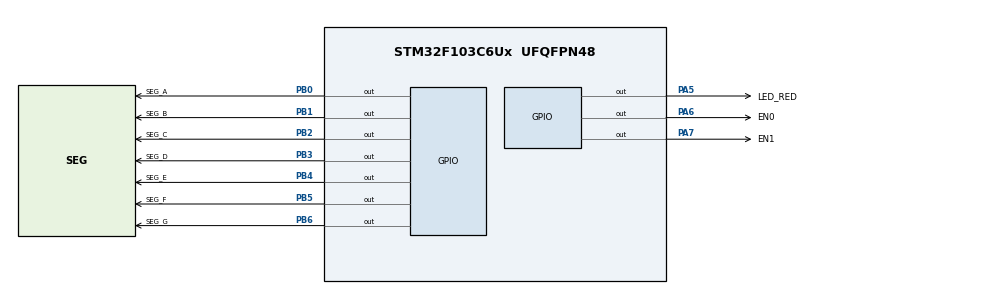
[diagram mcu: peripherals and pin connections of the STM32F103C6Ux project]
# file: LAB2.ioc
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Mcu.Family=STM32F1
Mcu.Name=STM32F103C6Ux
Mcu.Package=UFQFPN48
NVIC.PriorityGroup=NVIC_PRIORITYGROUP_4
NVIC.TIM2_IRQn=true\:0\:0\:false\:false\:true\:true\:true
PA5.GPIO_Label=LED_RED
PA5.Signal=GPIO_Output
PA6.GPIO_Label=EN0
PA6.Signal=GPIO_Output
PA7.GPIO_Label=EN1
PA7.Signal=GPIO_Output
PB0.GPIO_Label=SEG_A
PB0.Signal=GPIO_Output
PB1.GPIO_Label=SEG_B
PB1.Signal=GPIO_Output
PB2.GPIO_Label=SEG_C
PB2.Signal=GPIO_Output
PB3.GPIO_Label=SEG_D
PB3.Signal=GPIO_Output
PB4.GPIO_Label=SEG_E
PB4.Signal=GPIO_Output
PB5.GPIO_Label=SEG_F
PB5.Signal=GPIO_Output
PB6.GPIO_Label=SEG_G
PB6.Signal=GPIO_Output
ProjectManager.HeapSize=0x200
ProjectManager.StackSize=0x400
ProjectManager.TargetToolchain=STM32CubeIDE
RCC.APB1Freq_Value=8000000
RCC.APB2Freq_Value=8000000
TIM2.Period=9
TIM2.Prescaler=7999
VP_SYS_VS_ND.Mode=No_Debug
VP_TIM2_VS_ClockSourceINT.Mode=Internal
board=custom

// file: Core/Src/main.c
/* USER CODE BEGIN Header */
/**
  ******************************************************************************
  * @file           : main.c
  * @brief          : Main program body
  ******************************************************************************
  * @attention
  *
  * <h2><center>&copy; Copyright (c) 2025 STMicroelectronics.
  * All rights reserved.</center></h2>
  *
  * This software component is licensed by ST under BSD 3-Clause license,
  * the "License"; You may not use this file except in compliance with the
  * License. You may obtain a copy of the License at:
  *                        opensource.org/licenses/BSD-3-Clause
  *
  ******************************************************************************
  */
/* USER CODE END Header */
#include "main.h"

/* USER CODE BEGIN Includes */
#include "software_timer.h"
/* USER CODE END Includes */

TIM_HandleTypeDef htim2;

void SystemClock_Config(void);
static void MX_GPIO_Init(void);
static void MX_TIM2_Init(void);
/* USER CODE BEGIN PFP */
void updateClockBuffer(void);
void update7SEG(int index);
/* USER CODE END PFP */

/* USER CODE BEGIN 0 */
const int MAX_LED = 4;
int index_led = 0;
int led_buffer[4] = {0, 0, 0, 0};

int hour = 0, minute = 0, second = 0;
/* USER CODE END 0 */

int main(void)
{

  /* MCU Configuration--------------------------------------------------------*/

  /* Reset of all peripherals, Initializes the Flash interface and the Systick. */
  HAL_Init();

  /* Configure the system clock */
  SystemClock_Config();

  /* Initialize all configured peripherals */
  MX_GPIO_Init();
  MX_TIM2_Init();
  /* USER CODE BEGIN 2 */
  HAL_TIM_Base_Start_IT(&htim2);
  /* USER CODE END 2 */

  /* Infinite loop */
  /* USER CODE BEGIN WHILE */
  hour = 15; minute = 8; second = 50;
  updateClockBuffer();
  HAL_GPIO_WritePin(EN0_GPIO_Port, EN0_Pin, SET);
  HAL_GPIO_WritePin(EN1_GPIO_Port, EN1_Pin, SET);
  HAL_GPIO_WritePin(EN2_GPIO_Port, EN2_Pin, SET);
  HAL_GPIO_WritePin(EN3_GPIO_Port, EN3_Pin, SET);
  setTimer (0, 100); // LED Blinky
  setTimer (1, 100); // DOT
  setTimer (2, 100); // UPDATE TIME
  setTimer (3, 25);  // UPDATE 7SEG
  while (1)
  {
	  if (isTimerExpired(0)) {
		  HAL_GPIO_TogglePin(LED_RED_GPIO_Port, LED_RED_Pin);
		  setTimer (0, 100);
	  }

	  if (isTimerExpired(1)) {
		  HAL_GPIO_TogglePin(DOT_GPIO_Port, DOT_Pin);
		  setTimer (1, 100);
	  }

	  if (isTimerExpired(2)) {
		  second++;
		  if (second >= 60) {
			  second = 0;
			  minute++;
		  }
		  if (minute >= 60) {
			  minute = 0;
			  hour++;
		  }
		  if (hour >= 24) {
			  hour = 0;
		  }
		  updateClockBuffer();
		  setTimer (2, 100);
	  }

	  if (isTimerExpired(3)) {
		  update7SEG(index_led);
		  index_led++;
		  if (index_led >= MAX_LED) {
			  index_led = 0;
		  }
		  setTimer (3, 25);
	  }
    /* USER CODE END WHILE */

  }
}

void SystemClock_Config(void)
{
  RCC_OscInitTypeDef RCC_OscInitStruct = {0};
  RCC_ClkInitTypeDef RCC_ClkInitStruct = {0};

  /** Initializes the RCC Oscillators according to the specified parameters
  * in the RCC_OscInitTypeDef structure.
  */
  RCC_OscInitStruct.OscillatorType = RCC_OSCILLATORTYPE_HSI;
  RCC_OscInitStruct.HSIState = RCC_HSI_ON;
  RCC_OscInitStruct.HSICalibrationValue = RCC_HSICALIBRATION_DEFAULT;
  RCC_OscInitStruct.PLL.PLLState = RCC_PLL_NONE;
  if (HAL_RCC_OscConfig(&RCC_OscInitStruct) != HAL_OK)
  {
    Error_Handler();
  }
  /** Initializes the CPU, AHB and APB buses clocks
  */
  RCC_ClkInitStruct.ClockType = RCC_CLOCKTYPE_HCLK|RCC_CLOCKTYPE_SYSCLK
                              |RCC_CLOCKTYPE_PCLK1|RCC_CLOCKTYPE_PCLK2;
  RCC_ClkInitStruct.SYSCLKSource = RCC_SYSCLKSOURCE_HSI;
  RCC_ClkInitStruct.AHBCLKDivider = RCC_SYSCLK_DIV1;
  RCC_ClkInitStruct.APB1CLKDivider = RCC_HCLK_DIV1;
  RCC_ClkInitStruct.APB2CLKDivider = RCC_HCLK_DIV1;

  if (HAL_RCC_ClockConfig(&RCC_ClkInitStruct, FLASH_LATENCY_0) != HAL_OK)
  {
    Error_Handler();
  }
}

static void MX_TIM2_Init(void)
{

  TIM_ClockConfigTypeDef sClockSourceConfig = {0};
  TIM_MasterConfigTypeDef sMasterConfig = {0};

  htim2.Instance = TIM2;
  htim2.Init.Prescaler = 7999;
  htim2.Init.CounterMode = TIM_COUNTERMODE_UP;
  htim2.Init.Period = 9;
  htim2.Init.ClockDivision = TIM_CLOCKDIVISION_DIV1;
  htim2.Init.AutoReloadPreload = TIM_AUTORELOAD_PRELOAD_DISABLE;
  if (HAL_TIM_Base_Init(&htim2) != HAL_OK)
  {
    Error_Handler();
  }
  sClockSourceConfig.ClockSource = TIM_CLOCKSOURCE_INTERNAL;
  if (HAL_TIM_ConfigClockSource(&htim2, &sClockSourceConfig) != HAL_OK)
  {
    Error_Handler();
  }
  sMasterConfig.MasterOutputTrigger = TIM_TRGO_RESET;
  sMasterConfig.MasterSlaveMode = TIM_MASTERSLAVEMODE_DISABLE;
  if (HAL_TIMEx_MasterConfigSynchronization(&htim2, &sMasterConfig) != HAL_OK)
  {
    Error_Handler();
  }

}

static void MX_GPIO_Init(void)
{
  GPIO_InitTypeDef GPIO_InitStruct = {0};

  /* GPIO Ports Clock Enable */
  __HAL_RCC_GPIOA_CLK_ENABLE();
  __HAL_RCC_GPIOB_CLK_ENABLE();

  /*Configure GPIO pin Output Level */
  HAL_GPIO_WritePin(GPIOA, DOT_Pin|LED_RED_Pin|EN0_Pin|EN1_Pin
                          |EN2_Pin|EN3_Pin, GPIO_PIN_RESET);

  /*Configure GPIO pin Output Level */
  HAL_GPIO_WritePin(GPIOB, SEG_A_Pin|SEG_B_Pin|SEG_C_Pin|SEG_D_Pin
                          |SEG_E_Pin|SEG_F_Pin|SEG_G_Pin, GPIO_PIN_RESET);

  /*Configure GPIO pins : DOT_Pin LED_RED_Pin EN0_Pin EN1_Pin
                           EN2_Pin EN3_Pin */
  GPIO_InitStruct.Pin = DOT_Pin|LED_RED_Pin|EN0_Pin|EN1_Pin
                          |EN2_Pin|EN3_Pin;
  GPIO_InitStruct.Mode = GPIO_MODE_OUTPUT_PP;
  GPIO_InitStruct.Pull = GPIO_NOPULL;
  GPIO_InitStruct.Speed = GPIO_SPEED_FREQ_LOW;
  HAL_GPIO_Init(GPIOA, &GPIO_InitStruct);

  /*Configure GPIO pins : SEG_A_Pin SEG_B_Pin SEG_C_Pin SEG_D_Pin
                           SEG_E_Pin SEG_F_Pin SEG_G_Pin */
  GPIO_InitStruct.Pin = SEG_A_Pin|SEG_B_Pin|SEG_C_Pin|SEG_D_Pin
                          |SEG_E_Pin|SEG_F_Pin|SEG_G_Pin;
  GPIO_InitStruct.Mode = GPIO_MODE_OUTPUT_PP;
  GPIO_InitStruct.Pull = GPIO_NOPULL;
  GPIO_InitStruct.Speed = GPIO_SPEED_FREQ_LOW;
  HAL_GPIO_Init(GPIOB, &GPIO_InitStruct);

}

/* USER CODE BEGIN 4 */
void clear7SEG(){
	HAL_GPIO_WritePin(SEG_A_GPIO_Port, SEG_A_Pin, GPIO_PIN_SET);
	HAL_GPIO_WritePin(SEG_B_GPIO_Port, SEG_B_Pin, GPIO_PIN_SET);
	HAL_GPIO_WritePin(SEG_C_GPIO_Port, SEG_C_Pin, GPIO_PIN_SET);
	HAL_GPIO_WritePin(SEG_D_GPIO_Port, SEG_D_Pin, GPIO_PIN_SET);
	HAL_GPIO_WritePin(SEG_E_GPIO_Port, SEG_E_Pin, GPIO_PIN_SET);
	HAL_GPIO_WritePin(SEG_F_GPIO_Port, SEG_F_Pin, GPIO_PIN_SET);
	HAL_GPIO_WritePin(SEG_G_GPIO_Port, SEG_G_Pin, GPIO_PIN_SET);
}
void display7SEG(int num) {
	clear7SEG();
	switch(num) {
		case 0:
			HAL_GPIO_WritePin(SEG_A_GPIO_Port, SEG_A_Pin, GPIO_PIN_RESET);
	        HAL_GPIO_WritePin(SEG_B_GPIO_Port, SEG_B_Pin, GPIO_PIN_RESET);
	        HAL_GPIO_WritePin(SEG_C_GPIO_Port, SEG_C_Pin, GPIO_PIN_RESET);
	        HAL_GPIO_WritePin(SEG_D_GPIO_Port, SEG_D_Pin, GPIO_PIN_RESET);
	        HAL_GPIO_WritePin(SEG_E_GPIO_Port, SEG_E_Pin, GPIO_PIN_RESET);
	        HAL_GPIO_WritePin(SEG_F_GPIO_Port, SEG_F_Pin, GPIO_PIN_RESET);
	        break;
	    case 1:
	        HAL_GPIO_WritePin(SEG_B_GPIO_Port, SEG_B_Pin, GPIO_PIN_RESET);
	        HAL_GPIO_WritePin(SEG_C_GPIO_Port, SEG_C_Pin, GPIO_PIN_RESET);
	        break;
	    case 2:
	        HAL_GPIO_WritePin(SEG_A_GPIO_Port, SEG_A_Pin, GPIO_PIN_RESET);
	        HAL_GPIO_WritePin(SEG_B_GPIO_Port, SEG_B_Pin, GPIO_PIN_RESET);
	        HAL_GPIO_WritePin(SEG_D_GPIO_Port, SEG_D_Pin, GPIO_PIN_RESET);
	        HAL_GPIO_WritePin(SEG_E_GPIO_Port, SEG_E_Pin, GPIO_PIN_RESET);
	        HAL_GPIO_WritePin(SEG_G_GPIO_Port, SEG_G_Pin, GPIO_PIN_RESET);
	        break;
	    case 3:
	        HAL_GPIO_WritePin(SEG_A_GPIO_Port, SEG_A_Pin, GPIO_PIN_RESET);
	        HAL_GPIO_WritePin(SEG_B_GPIO_Port, SEG_B_Pin, GPIO_PIN_RESET);
	        HAL_GPIO_WritePin(SEG_C_GPIO_Port, SEG_C_Pin, GPIO_PIN_RESET);
	        HAL_GPIO_WritePin(SEG_D_GPIO_Port, SEG_D_Pin, GPIO_PIN_RESET);
	        HAL_GPIO_WritePin(SEG_G_GPIO_Port, SEG_G_Pin, GPIO_PIN_RESET);
	        break;
	    case 4:
	        HAL_GPIO_WritePin(SEG_B_GPIO_Port, SEG_B_Pin, GPIO_PIN_RESET);
	        HAL_GPIO_WritePin(SEG_C_GPIO_Port, SEG_C_Pin, GPIO_PIN_RESET);
	        HAL_GPIO_WritePin(SEG_F_GPIO_Port, SEG_F_Pin, GPIO_PIN_RESET);
	        HAL_GPIO_WritePin(SEG_G_GPIO_Port, SEG_G_Pin, GPIO_PIN_RESET);
	        break;
	    case 5:
	        HAL_GPIO_WritePin(SEG_A_GPIO_Port, SEG_A_Pin, GPIO_PIN_RESET);
	        HAL_GPIO_WritePin(SEG_C_GPIO_Port, SEG_C_Pin, GPIO_PIN_RESET);
	        HAL_GPIO_WritePin(SEG_D_GPIO_Port, SEG_D_Pin, GPIO_PIN_RESET);
	        HAL_GPIO_WritePin(SEG_F_GPIO_Port, SEG_F_Pin, GPIO_PIN_RESET);
	        HAL_GPIO_WritePin(SEG_G_GPIO_Port, SEG_G_Pin, GPIO_PIN_RESET);
	        break;
	    case 6:
	        HAL_GPIO_WritePin(SEG_A_GPIO_Port, SEG_A_Pin, GPIO_PIN_RESET);
	        HAL_GPIO_WritePin(SEG_C_GPIO_Port, SEG_C_Pin, GPIO_PIN_RESET);
	        HAL_GPIO_WritePin(SEG_D_GPIO_Port, SEG_D_Pin, GPIO_PIN_RESET);
	        HAL_GPIO_WritePin(SEG_E_GPIO_Port, SEG_E_Pin, GPIO_PIN_RESET);
	        HAL_GPIO_WritePin(SEG_F_GPIO_Port, SEG_F_Pin, GPIO_PIN_RESET);
	        HAL_GPIO_WritePin(SEG_G_GPIO_Port, SEG_G_Pin, GPIO_PIN_RESET);
	        break;
	    case 7:
	        HAL_GPIO_WritePin(SEG_A_GPIO_Port, SEG_A_Pin, GPIO_PIN_RESET);
	        HAL_GPIO_WritePin(SEG_B_GPIO_Port, SEG_B_Pin, GPIO_PIN_RESET);
	        HAL_GPIO_WritePin(SEG_C_GPIO_Port, SEG_C_Pin, GPIO_PIN_RESET);
	        break;
	    case 8:
	        HAL_GPIO_WritePin(SEG_A_GPIO_Port, SEG_A_Pin, GPIO_PIN_RESET);
	        HAL_GPIO_WritePin(SEG_B_GPIO_Port, SEG_B_Pin, GPIO_PIN_RESET);
	        HAL_GPIO_WritePin(SEG_C_GPIO_Port, SEG_C_Pin, GPIO_PIN_RESET);
	        HAL_GPIO_WritePin(SEG_D_GPIO_Port, SEG_D_Pin, GPIO_PIN_RESET);
	        HAL_GPIO_WritePin(SEG_E_GPIO_Port, SEG_E_Pin, GPIO_PIN_RESET);
	        HAL_GPIO_WritePin(SEG_F_GPIO_Port, SEG_F_Pin, GPIO_PIN_RESET);
	        HAL_GPIO_WritePin(SEG_G_GPIO_Port, SEG_G_Pin, GPIO_PIN_RESET);
	        break;
	    case 9:
	        HAL_GPIO_WritePin(SEG_A_GPIO_Port, SEG_A_Pin, GPIO_PIN_RESET);
	        HAL_GPIO_WritePin(SEG_B_GPIO_Port, SEG_B_Pin, GPIO_PIN_RESET);
	        HAL_GPIO_WritePin(SEG_C_GPIO_Port, SEG_C_Pin, GPIO_PIN_RESET);
	        HAL_GPIO_WritePin(SEG_D_GPIO_Port, SEG_D_Pin, GPIO_PIN_RESET);
	        HAL_GPIO_WritePin(SEG_F_GPIO_Port, SEG_F_Pin, GPIO_PIN_RESET);
	        HAL_GPIO_WritePin(SEG_G_GPIO_Port, SEG_G_Pin, GPIO_PIN_RESET);
	        break;
	    default:
	        break;
	}
}

void update7SEG(int index) {
    switch(index) {
        case 0:
            // Display the first 7 SEG with led_buffer[0]
            display7SEG(led_buffer[0]);
            // Turn off all other displays
            HAL_GPIO_WritePin(EN0_GPIO_Port, EN0_Pin, GPIO_PIN_RESET);
            HAL_GPIO_WritePin(EN1_GPIO_Port, EN1_Pin, GPIO_PIN_SET);
            HAL_GPIO_WritePin(EN2_GPIO_Port, EN2_Pin, GPIO_PIN_SET);
            HAL_GPIO_WritePin(EN3_GPIO_Port, EN3_Pin, GPIO_PIN_SET);
            break;
        case 1:
            // Display the second 7 SEG with led_buffer[1]
            display7SEG(led_buffer[1]);
            HAL_GPIO_WritePin(EN0_GPIO_Port, EN0_Pin, GPIO_PIN_SET);
            HAL_GPIO_WritePin(EN1_GPIO_Port, EN1_Pin, GPIO_PIN_RESET);
            HAL_GPIO_WritePin(EN2_GPIO_Port, EN2_Pin, GPIO_PIN_SET);
            HAL_GPIO_WritePin(EN3_GPIO_Port, EN3_Pin, GPIO_PIN_SET);
            break;
        case 2:
            // Display the third 7 SEG with led_buffer[2]
            display7SEG(led_buffer[2]);
            HAL_GPIO_WritePin(EN0_GPIO_Port, EN0_Pin, GPIO_PIN_SET);
            HAL_GPIO_WritePin(EN1_GPIO_Port, EN1_Pin, GPIO_PIN_SET);
            HAL_GPIO_WritePin(EN2_GPIO_Port, EN2_Pin, GPIO_PIN_RESET);
            HAL_GPIO_WritePin(EN3_GPIO_Port, EN3_Pin, GPIO_PIN_SET);
            break;
        case 3:
            // Display the fourth 7 SEG with led_buffer[3]
            display7SEG(led_buffer[3]);
            HAL_GPIO_WritePin(EN0_GPIO_Port, EN0_Pin, GPIO_PIN_SET);
            HAL_GPIO_WritePin(EN1_GPIO_Port, EN1_Pin, GPIO_PIN_SET);
            HAL_GPIO_WritePin(EN2_GPIO_Port, EN2_Pin, GPIO_PIN_SET);
            HAL_GPIO_WritePin(EN3_GPIO_Port, EN3_Pin, GPIO_PIN_RESET);
            break;
        default:
            break;
    }
}

void updateClockBuffer() {
    // led_buffer[0] = hour tens digit
    // led_buffer[1] = hour units digit
    // led_buffer[2] = minute tens digit
    // led_buffer[3] = minute units digit

    led_buffer[0] = hour / 10;
    led_buffer[1] = hour % 10;
    led_buffer[2] = minute / 10;
    led_buffer[3] = minute % 10;
}

void HAL_TIM_PeriodElapsedCallback(TIM_HandleTypeDef *htim)
{
	timerRun();
}
/* USER CODE END 4 */

void Error_Handler(void)
{
  __disable_irq();
  while (1)
  {
  }
}

/************************ (C) COPYRIGHT STMicroelectronics *****END OF FILE****/
